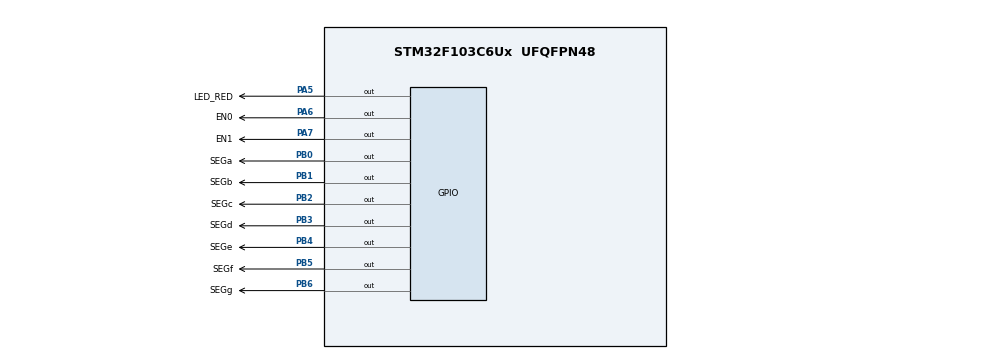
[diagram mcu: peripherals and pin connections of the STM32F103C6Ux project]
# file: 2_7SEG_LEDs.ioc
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Mcu.Family=STM32F1
Mcu.Name=STM32F103C6Ux
Mcu.Package=UFQFPN48
NVIC.PriorityGroup=NVIC_PRIORITYGROUP_4
NVIC.TIM2_IRQn=true\:0\:0\:false\:false\:true\:true\:true
PA5.GPIO_Label=LED_RED
PA5.Signal=GPIO_Output
PA6.GPIO_Label=EN0
PA6.Signal=GPIO_Output
PA7.GPIO_Label=EN1
PA7.Signal=GPIO_Output
PB0.GPIO_Label=SEGa
PB0.Signal=GPIO_Output
PB1.GPIO_Label=SEGb
PB1.Signal=GPIO_Output
PB2.GPIO_Label=SEGc
PB2.Signal=GPIO_Output
PB3.GPIO_Label=SEGd
PB3.Signal=GPIO_Output
PB4.GPIO_Label=SEGe
PB4.Signal=GPIO_Output
PB5.GPIO_Label=SEGf
PB5.Signal=GPIO_Output
PB6.GPIO_Label=SEGg
PB6.Signal=GPIO_Output
ProjectManager.HeapSize=0x200
ProjectManager.StackSize=0x400
ProjectManager.TargetToolchain=STM32CubeIDE
RCC.APB1Freq_Value=8000000
RCC.APB2Freq_Value=8000000
TIM2.Period=9
TIM2.Prescaler=7999
VP_SYS_VS_ND.Mode=No_Debug
VP_TIM2_VS_ClockSourceINT.Mode=Internal
board=custom

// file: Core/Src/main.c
/* USER CODE BEGIN Header */
/**
  ******************************************************************************
  * @file           : main.c
  * @brief          : Main program body
  ******************************************************************************
  * @attention
  *
  * <h2><center>&copy; Copyright (c) 2023 STMicroelectronics.
  * All rights reserved.</center></h2>
  *
  * This software component is licensed by ST under BSD 3-Clause license,
  * the "License"; You may not use this file except in compliance with the
  * License. You may obtain a copy of the License at:
  *                        opensource.org/licenses/BSD-3-Clause
  *
  ******************************************************************************
  */
/* USER CODE END Header */
#include "main.h"

TIM_HandleTypeDef htim2;

void SystemClock_Config(void);
static void MX_GPIO_Init(void);
static void MX_TIM2_Init(void);

/* USER CODE BEGIN 0 */
void display7SEG(int num){
	const uint8_t sevenSegment[10] = {	0b00111111, // 0
										0b00000110, // 1
										0b01011011, // 2
										0b01001111, // 3
										0b01100110, // 4
										0b01101101, // 5
										0b01111101, // 6
										0b00000111, // 7
										0b01111111, // 8
										0b01101111  // 9
	};
	HAL_GPIO_WritePin(SEGa_GPIO_Port, SEGa_Pin, ((sevenSegment[num]) & 0x01) ? RESET : SET);
	HAL_GPIO_WritePin(SEGb_GPIO_Port, SEGb_Pin, ((sevenSegment[num] >> 1) & 0x01) ? RESET : SET);
	HAL_GPIO_WritePin(SEGc_GPIO_Port, SEGc_Pin, ((sevenSegment[num] >> 2) & 0x01) ? RESET : SET);
	HAL_GPIO_WritePin(SEGd_GPIO_Port, SEGd_Pin, ((sevenSegment[num] >> 3) & 0x01) ? RESET : SET);
	HAL_GPIO_WritePin(SEGe_GPIO_Port, SEGe_Pin, ((sevenSegment[num] >> 4) & 0x01) ? RESET : SET);
	HAL_GPIO_WritePin(SEGf_GPIO_Port, SEGf_Pin, ((sevenSegment[num] >> 5) & 0x01) ? RESET : SET);
	HAL_GPIO_WritePin(SEGg_GPIO_Port, SEGg_Pin, ((sevenSegment[num] >> 6) & 0x01) ? RESET : SET);
}
/* USER CODE END 0 */

int main(void)
{

  /* MCU Configuration--------------------------------------------------------*/

  /* Reset of all peripherals, Initializes the Flash interface and the Systick. */
  HAL_Init();

  /* Configure the system clock */
  SystemClock_Config();

  /* Initialize all configured peripherals */
  MX_GPIO_Init();
  MX_TIM2_Init();
  /* USER CODE BEGIN 2 */
  HAL_TIM_Base_Start_IT(&htim2);
  /* USER CODE END 2 */

  /* Infinite loop */
  while (1)
  {

  }
}

void SystemClock_Config(void)
{
  RCC_OscInitTypeDef RCC_OscInitStruct = {0};
  RCC_ClkInitTypeDef RCC_ClkInitStruct = {0};

  /** Initializes the RCC Oscillators according to the specified parameters
  * in the RCC_OscInitTypeDef structure.
  */
  RCC_OscInitStruct.OscillatorType = RCC_OSCILLATORTYPE_HSI;
  RCC_OscInitStruct.HSIState = RCC_HSI_ON;
  RCC_OscInitStruct.HSICalibrationValue = RCC_HSICALIBRATION_DEFAULT;
  RCC_OscInitStruct.PLL.PLLState = RCC_PLL_NONE;
  if (HAL_RCC_OscConfig(&RCC_OscInitStruct) != HAL_OK)
  {
    Error_Handler();
  }
  /** Initializes the CPU, AHB and APB buses clocks
  */
  RCC_ClkInitStruct.ClockType = RCC_CLOCKTYPE_HCLK|RCC_CLOCKTYPE_SYSCLK
                              |RCC_CLOCKTYPE_PCLK1|RCC_CLOCKTYPE_PCLK2;
  RCC_ClkInitStruct.SYSCLKSource = RCC_SYSCLKSOURCE_HSI;
  RCC_ClkInitStruct.AHBCLKDivider = RCC_SYSCLK_DIV1;
  RCC_ClkInitStruct.APB1CLKDivider = RCC_HCLK_DIV1;
  RCC_ClkInitStruct.APB2CLKDivider = RCC_HCLK_DIV1;

  if (HAL_RCC_ClockConfig(&RCC_ClkInitStruct, FLASH_LATENCY_0) != HAL_OK)
  {
    Error_Handler();
  }
}

static void MX_TIM2_Init(void)
{

  TIM_ClockConfigTypeDef sClockSourceConfig = {0};
  TIM_MasterConfigTypeDef sMasterConfig = {0};

  htim2.Instance = TIM2;
  htim2.Init.Prescaler = 7999;
  htim2.Init.CounterMode = TIM_COUNTERMODE_UP;
  htim2.Init.Period = 9;
  htim2.Init.ClockDivision = TIM_CLOCKDIVISION_DIV1;
  htim2.Init.AutoReloadPreload = TIM_AUTORELOAD_PRELOAD_DISABLE;
  if (HAL_TIM_Base_Init(&htim2) != HAL_OK)
  {
    Error_Handler();
  }
  sClockSourceConfig.ClockSource = TIM_CLOCKSOURCE_INTERNAL;
  if (HAL_TIM_ConfigClockSource(&htim2, &sClockSourceConfig) != HAL_OK)
  {
    Error_Handler();
  }
  sMasterConfig.MasterOutputTrigger = TIM_TRGO_RESET;
  sMasterConfig.MasterSlaveMode = TIM_MASTERSLAVEMODE_DISABLE;
  if (HAL_TIMEx_MasterConfigSynchronization(&htim2, &sMasterConfig) != HAL_OK)
  {
    Error_Handler();
  }

}

static void MX_GPIO_Init(void)
{
  GPIO_InitTypeDef GPIO_InitStruct = {0};

  /* GPIO Ports Clock Enable */
  __HAL_RCC_GPIOA_CLK_ENABLE();
  __HAL_RCC_GPIOB_CLK_ENABLE();

  /*Configure GPIO pin Output Level */
  HAL_GPIO_WritePin(GPIOA, DOT_Pin|LED_RED_Pin|EN0_Pin|EN2_Pin
                          |EN3_Pin, GPIO_PIN_RESET);

  /*Configure GPIO pin Output Level */
  HAL_GPIO_WritePin(GPIOB, SEGa_Pin|SEGb_Pin|SEGc_Pin|SEGd_Pin
                          |SEGe_Pin|SEGf_Pin|SEGg_Pin, GPIO_PIN_RESET);

  /*Configure GPIO pins : DOT_Pin LED_RED_Pin EN0_Pin EN2_Pin
                           EN3_Pin */
  GPIO_InitStruct.Pin = DOT_Pin|LED_RED_Pin|EN0_Pin|EN2_Pin
                          |EN3_Pin;
  GPIO_InitStruct.Mode = GPIO_MODE_OUTPUT_PP;
  GPIO_InitStruct.Pull = GPIO_NOPULL;
  GPIO_InitStruct.Speed = GPIO_SPEED_FREQ_LOW;
  HAL_GPIO_Init(GPIOA, &GPIO_InitStruct);

  /*Configure GPIO pin : EN1_Pin */
  GPIO_InitStruct.Pin = EN1_Pin;
  GPIO_InitStruct.Mode = GPIO_MODE_ANALOG;
  HAL_GPIO_Init(EN1_GPIO_Port, &GPIO_InitStruct);

  /*Configure GPIO pins : SEGa_Pin SEGb_Pin SEGc_Pin SEGd_Pin
                           SEGe_Pin SEGf_Pin SEGg_Pin */
  GPIO_InitStruct.Pin = SEGa_Pin|SEGb_Pin|SEGc_Pin|SEGd_Pin
                          |SEGe_Pin|SEGf_Pin|SEGg_Pin;
  GPIO_InitStruct.Mode = GPIO_MODE_OUTPUT_PP;
  GPIO_InitStruct.Pull = GPIO_NOPULL;
  GPIO_InitStruct.Speed = GPIO_SPEED_FREQ_LOW;
  HAL_GPIO_Init(GPIOB, &GPIO_InitStruct);

}

/* USER CODE BEGIN 4 */
int counter1 = 0, counter2 = 100, state = 1;
void HAL_TIM_PeriodElapsedCallback(TIM_HandleTypeDef *htim){
	counter1--;
	if(counter1 <= 0){
		counter1 = 100;
		switch(state){
		case 1:
		  HAL_GPIO_WritePin(EN0_GPIO_Port, EN0_Pin, RESET);
		  HAL_GPIO_WritePin(EN1_GPIO_Port, EN1_Pin, SET);
		  HAL_GPIO_WritePin(EN2_GPIO_Port, EN2_Pin, SET);
		  HAL_GPIO_WritePin(EN3_GPIO_Port, EN3_Pin, SET);
		  display7SEG(1);
		  state = 2;
		  break;
		case 2:
		  HAL_GPIO_WritePin(EN0_GPIO_Port, EN0_Pin, SET);
		  HAL_GPIO_WritePin(EN1_GPIO_Port, EN1_Pin, RESET);
		  HAL_GPIO_WritePin(EN2_GPIO_Port, EN2_Pin, SET);
		  HAL_GPIO_WritePin(EN3_GPIO_Port, EN3_Pin, SET);
		  display7SEG(2);
		  state = 3;
		case 3:
		  HAL_GPIO_WritePin(EN0_GPIO_Port, EN0_Pin, SET);
		  HAL_GPIO_WritePin(EN1_GPIO_Port, EN1_Pin, SET);
		  HAL_GPIO_WritePin(EN2_GPIO_Port, EN2_Pin, RESET);
		  HAL_GPIO_WritePin(EN3_GPIO_Port, EN3_Pin, SET);
		  display7SEG(3);
		  state = 0;
		  break;
		case 0:
		  HAL_GPIO_WritePin(EN0_GPIO_Port, EN0_Pin, SET);
		  HAL_GPIO_WritePin(EN1_GPIO_Port, EN1_Pin, SET);
		  HAL_GPIO_WritePin(EN2_GPIO_Port, EN2_Pin, SET);
		  HAL_GPIO_WritePin(EN3_GPIO_Port, EN3_Pin, RESET);
		  display7SEG(0);
		  state = 1;
		  break;
		default:
		  break;
		}
	  }
	counter2--;
	if(counter2 <= 0){
		counter2 = 200;
		HAL_GPIO_TogglePin(DOT_GPIO_Port, DOT_Pin);
	}
}
/* USER CODE END 4 */

void Error_Handler(void)
{
  __disable_irq();
  while (1)
  {
  }
}

/************************ (C) COPYRIGHT STMicroelectronics *****END OF FILE****/
